VERSION 5.7 ;
BUSBITCHARS "[]" ;
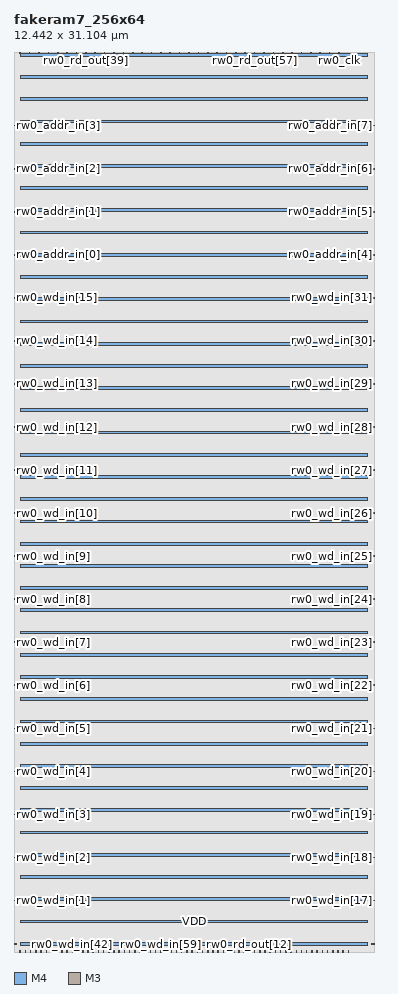
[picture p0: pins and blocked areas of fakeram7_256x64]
MACRO fakeram7_256x64
  FOREIGN fakeram7_256x64 0 0 ;
  SYMMETRY X Y R90 ;
  SIZE 12.442 BY 31.104 ;
  CLASS BLOCK ;
  PIN rw0_wd_in[0]
    DIRECTION INPUT ;
    USE SIGNAL ;
    SHAPE ABUTMENT ;
    PORT
      LAYER M4 ;
      RECT 0.000 0.276 0.072 0.300 ;
    END
  END rw0_wd_in[0]
  PIN rw0_wd_in[1]
    DIRECTION INPUT ;
    USE SIGNAL ;
    SHAPE ABUTMENT ;
    PORT
      LAYER M4 ;
      RECT 0.000 1.764 0.072 1.788 ;
    END
  END rw0_wd_in[1]
  PIN rw0_wd_in[2]
    DIRECTION INPUT ;
    USE SIGNAL ;
    SHAPE ABUTMENT ;
    PORT
      LAYER M4 ;
      RECT 0.000 3.252 0.072 3.276 ;
    END
  END rw0_wd_in[2]
  PIN rw0_wd_in[3]
    DIRECTION INPUT ;
    USE SIGNAL ;
    SHAPE ABUTMENT ;
    PORT
      LAYER M4 ;
      RECT 0.000 4.740 0.072 4.764 ;
    END
  END rw0_wd_in[3]
  PIN rw0_wd_in[4]
    DIRECTION INPUT ;
    USE SIGNAL ;
    SHAPE ABUTMENT ;
    PORT
      LAYER M4 ;
      RECT 0.000 6.228 0.072 6.252 ;
    END
  END rw0_wd_in[4]
  PIN rw0_wd_in[5]
    DIRECTION INPUT ;
    USE SIGNAL ;
    SHAPE ABUTMENT ;
    PORT
      LAYER M4 ;
      RECT 0.000 7.716 0.072 7.740 ;
    END
  END rw0_wd_in[5]
  PIN rw0_wd_in[6]
    DIRECTION INPUT ;
    USE SIGNAL ;
    SHAPE ABUTMENT ;
    PORT
      LAYER M4 ;
      RECT 0.000 9.204 0.072 9.228 ;
    END
  END rw0_wd_in[6]
  PIN rw0_wd_in[7]
    DIRECTION INPUT ;
    USE SIGNAL ;
    SHAPE ABUTMENT ;
    PORT
      LAYER M4 ;
      RECT 0.000 10.692 0.072 10.716 ;
    END
  END rw0_wd_in[7]
  PIN rw0_wd_in[8]
    DIRECTION INPUT ;
    USE SIGNAL ;
    SHAPE ABUTMENT ;
    PORT
      LAYER M4 ;
      RECT 0.000 12.180 0.072 12.204 ;
    END
  END rw0_wd_in[8]
  PIN rw0_wd_in[9]
    DIRECTION INPUT ;
    USE SIGNAL ;
    SHAPE ABUTMENT ;
    PORT
      LAYER M4 ;
      RECT 0.000 13.668 0.072 13.692 ;
    END
  END rw0_wd_in[9]
  PIN rw0_wd_in[10]
    DIRECTION INPUT ;
    USE SIGNAL ;
    SHAPE ABUTMENT ;
    PORT
      LAYER M4 ;
      RECT 0.000 15.156 0.072 15.180 ;
    END
  END rw0_wd_in[10]
  PIN rw0_wd_in[11]
    DIRECTION INPUT ;
    USE SIGNAL ;
    SHAPE ABUTMENT ;
    PORT
      LAYER M4 ;
      RECT 0.000 16.644 0.072 16.668 ;
    END
  END rw0_wd_in[11]
  PIN rw0_wd_in[12]
    DIRECTION INPUT ;
    USE SIGNAL ;
    SHAPE ABUTMENT ;
    PORT
      LAYER M4 ;
      RECT 0.000 18.132 0.072 18.156 ;
    END
  END rw0_wd_in[12]
  PIN rw0_wd_in[13]
    DIRECTION INPUT ;
    USE SIGNAL ;
    SHAPE ABUTMENT ;
    PORT
      LAYER M4 ;
      RECT 0.000 19.620 0.072 19.644 ;
    END
  END rw0_wd_in[13]
  PIN rw0_wd_in[14]
    DIRECTION INPUT ;
    USE SIGNAL ;
    SHAPE ABUTMENT ;
    PORT
      LAYER M4 ;
      RECT 0.000 21.108 0.072 21.132 ;
    END
  END rw0_wd_in[14]
  PIN rw0_wd_in[15]
    DIRECTION INPUT ;
    USE SIGNAL ;
    SHAPE ABUTMENT ;
    PORT
      LAYER M4 ;
      RECT 0.000 22.596 0.072 22.620 ;
    END
  END rw0_wd_in[15]
  PIN rw0_wd_in[16]
    DIRECTION INPUT ;
    USE SIGNAL ;
    SHAPE ABUTMENT ;
    PORT
      LAYER M4 ;
      RECT 12.370 0.276 12.442 0.300 ;
    END
  END rw0_wd_in[16]
  PIN rw0_wd_in[17]
    DIRECTION INPUT ;
    USE SIGNAL ;
    SHAPE ABUTMENT ;
    PORT
      LAYER M4 ;
      RECT 12.370 1.764 12.442 1.788 ;
    END
  END rw0_wd_in[17]
  PIN rw0_wd_in[18]
    DIRECTION INPUT ;
    USE SIGNAL ;
    SHAPE ABUTMENT ;
    PORT
      LAYER M4 ;
      RECT 12.370 3.252 12.442 3.276 ;
    END
  END rw0_wd_in[18]
  PIN rw0_wd_in[19]
    DIRECTION INPUT ;
    USE SIGNAL ;
    SHAPE ABUTMENT ;
    PORT
      LAYER M4 ;
      RECT 12.370 4.740 12.442 4.764 ;
    END
  END rw0_wd_in[19]
  PIN rw0_wd_in[20]
    DIRECTION INPUT ;
    USE SIGNAL ;
    SHAPE ABUTMENT ;
    PORT
      LAYER M4 ;
      RECT 12.370 6.228 12.442 6.252 ;
    END
  END rw0_wd_in[20]
  PIN rw0_wd_in[21]
    DIRECTION INPUT ;
    USE SIGNAL ;
    SHAPE ABUTMENT ;
    PORT
      LAYER M4 ;
      RECT 12.370 7.716 12.442 7.740 ;
    END
  END rw0_wd_in[21]
  PIN rw0_wd_in[22]
    DIRECTION INPUT ;
    USE SIGNAL ;
    SHAPE ABUTMENT ;
    PORT
      LAYER M4 ;
      RECT 12.370 9.204 12.442 9.228 ;
    END
  END rw0_wd_in[22]
  PIN rw0_wd_in[23]
    DIRECTION INPUT ;
    USE SIGNAL ;
    SHAPE ABUTMENT ;
    PORT
      LAYER M4 ;
      RECT 12.370 10.692 12.442 10.716 ;
    END
  END rw0_wd_in[23]
  PIN rw0_wd_in[24]
    DIRECTION INPUT ;
    USE SIGNAL ;
    SHAPE ABUTMENT ;
    PORT
      LAYER M4 ;
      RECT 12.370 12.180 12.442 12.204 ;
    END
  END rw0_wd_in[24]
  PIN rw0_wd_in[25]
    DIRECTION INPUT ;
    USE SIGNAL ;
    SHAPE ABUTMENT ;
    PORT
      LAYER M4 ;
      RECT 12.370 13.668 12.442 13.692 ;
    END
  END rw0_wd_in[25]
  PIN rw0_wd_in[26]
    DIRECTION INPUT ;
    USE SIGNAL ;
    SHAPE ABUTMENT ;
    PORT
      LAYER M4 ;
      RECT 12.370 15.156 12.442 15.180 ;
    END
  END rw0_wd_in[26]
  PIN rw0_wd_in[27]
    DIRECTION INPUT ;
    USE SIGNAL ;
    SHAPE ABUTMENT ;
    PORT
      LAYER M4 ;
      RECT 12.370 16.644 12.442 16.668 ;
    END
  END rw0_wd_in[27]
  PIN rw0_wd_in[28]
    DIRECTION INPUT ;
    USE SIGNAL ;
    SHAPE ABUTMENT ;
    PORT
      LAYER M4 ;
      RECT 12.370 18.132 12.442 18.156 ;
    END
  END rw0_wd_in[28]
  PIN rw0_wd_in[29]
    DIRECTION INPUT ;
    USE SIGNAL ;
    SHAPE ABUTMENT ;
    PORT
      LAYER M4 ;
      RECT 12.370 19.620 12.442 19.644 ;
    END
  END rw0_wd_in[29]
  PIN rw0_wd_in[30]
    DIRECTION INPUT ;
    USE SIGNAL ;
    SHAPE ABUTMENT ;
    PORT
      LAYER M4 ;
      RECT 12.370 21.108 12.442 21.132 ;
    END
  END rw0_wd_in[30]
  PIN rw0_wd_in[31]
    DIRECTION INPUT ;
    USE SIGNAL ;
    SHAPE ABUTMENT ;
    PORT
      LAYER M4 ;
      RECT 12.370 22.596 12.442 22.620 ;
    END
  END rw0_wd_in[31]
  PIN rw0_wd_in[32]
    DIRECTION OUTPUT ;
    USE SIGNAL ;
    SHAPE ABUTMENT ;
    PORT
      LAYER M3 ;
      RECT 0.207 0.000 0.225 0.054 ;
    END
  END rw0_wd_in[32]
  PIN rw0_wd_in[33]
    DIRECTION OUTPUT ;
    USE SIGNAL ;
    SHAPE ABUTMENT ;
    PORT
      LAYER M3 ;
      RECT 0.387 0.000 0.405 0.054 ;
    END
  END rw0_wd_in[33]
  PIN rw0_wd_in[34]
    DIRECTION OUTPUT ;
    USE SIGNAL ;
    SHAPE ABUTMENT ;
    PORT
      LAYER M3 ;
      RECT 0.567 0.000 0.585 0.054 ;
    END
  END rw0_wd_in[34]
  PIN rw0_wd_in[35]
    DIRECTION OUTPUT ;
    USE SIGNAL ;
    SHAPE ABUTMENT ;
    PORT
      LAYER M3 ;
      RECT 0.747 0.000 0.765 0.054 ;
    END
  END rw0_wd_in[35]
  PIN rw0_wd_in[36]
    DIRECTION OUTPUT ;
    USE SIGNAL ;
    SHAPE ABUTMENT ;
    PORT
      LAYER M3 ;
      RECT 0.927 0.000 0.945 0.054 ;
    END
  END rw0_wd_in[36]
  PIN rw0_wd_in[37]
    DIRECTION OUTPUT ;
    USE SIGNAL ;
    SHAPE ABUTMENT ;
    PORT
      LAYER M3 ;
      RECT 1.107 0.000 1.125 0.054 ;
    END
  END rw0_wd_in[37]
  PIN rw0_wd_in[38]
    DIRECTION OUTPUT ;
    USE SIGNAL ;
    SHAPE ABUTMENT ;
    PORT
      LAYER M3 ;
      RECT 1.287 0.000 1.305 0.054 ;
    END
  END rw0_wd_in[38]
  PIN rw0_wd_in[39]
    DIRECTION OUTPUT ;
    USE SIGNAL ;
    SHAPE ABUTMENT ;
    PORT
      LAYER M3 ;
      RECT 1.467 0.000 1.485 0.054 ;
    END
  END rw0_wd_in[39]
  PIN rw0_wd_in[40]
    DIRECTION OUTPUT ;
    USE SIGNAL ;
    SHAPE ABUTMENT ;
    PORT
      LAYER M3 ;
      RECT 1.647 0.000 1.665 0.054 ;
    END
  END rw0_wd_in[40]
  PIN rw0_wd_in[41]
    DIRECTION OUTPUT ;
    USE SIGNAL ;
    SHAPE ABUTMENT ;
    PORT
      LAYER M3 ;
      RECT 1.827 0.000 1.845 0.054 ;
    END
  END rw0_wd_in[41]
  PIN rw0_wd_in[42]
    DIRECTION OUTPUT ;
    USE SIGNAL ;
    SHAPE ABUTMENT ;
    PORT
      LAYER M3 ;
      RECT 2.007 0.000 2.025 0.054 ;
    END
  END rw0_wd_in[42]
  PIN rw0_wd_in[43]
    DIRECTION OUTPUT ;
    USE SIGNAL ;
    SHAPE ABUTMENT ;
    PORT
      LAYER M3 ;
      RECT 2.187 0.000 2.205 0.054 ;
    END
  END rw0_wd_in[43]
  PIN rw0_wd_in[44]
    DIRECTION OUTPUT ;
    USE SIGNAL ;
    SHAPE ABUTMENT ;
    PORT
      LAYER M3 ;
      RECT 2.367 0.000 2.385 0.054 ;
    END
  END rw0_wd_in[44]
  PIN rw0_wd_in[45]
    DIRECTION OUTPUT ;
    USE SIGNAL ;
    SHAPE ABUTMENT ;
    PORT
      LAYER M3 ;
      RECT 2.547 0.000 2.565 0.054 ;
    END
  END rw0_wd_in[45]
  PIN rw0_wd_in[46]
    DIRECTION OUTPUT ;
    USE SIGNAL ;
    SHAPE ABUTMENT ;
    PORT
      LAYER M3 ;
      RECT 2.727 0.000 2.745 0.054 ;
    END
  END rw0_wd_in[46]
  PIN rw0_wd_in[47]
    DIRECTION OUTPUT ;
    USE SIGNAL ;
    SHAPE ABUTMENT ;
    PORT
      LAYER M3 ;
      RECT 2.907 0.000 2.925 0.054 ;
    END
  END rw0_wd_in[47]
  PIN rw0_wd_in[48]
    DIRECTION OUTPUT ;
    USE SIGNAL ;
    SHAPE ABUTMENT ;
    PORT
      LAYER M3 ;
      RECT 3.087 0.000 3.105 0.054 ;
    END
  END rw0_wd_in[48]
  PIN rw0_wd_in[49]
    DIRECTION OUTPUT ;
    USE SIGNAL ;
    SHAPE ABUTMENT ;
    PORT
      LAYER M3 ;
      RECT 3.267 0.000 3.285 0.054 ;
    END
  END rw0_wd_in[49]
  PIN rw0_wd_in[50]
    DIRECTION OUTPUT ;
    USE SIGNAL ;
    SHAPE ABUTMENT ;
    PORT
      LAYER M3 ;
      RECT 3.447 0.000 3.465 0.054 ;
    END
  END rw0_wd_in[50]
  PIN rw0_wd_in[51]
    DIRECTION OUTPUT ;
    USE SIGNAL ;
    SHAPE ABUTMENT ;
    PORT
      LAYER M3 ;
      RECT 3.627 0.000 3.645 0.054 ;
    END
  END rw0_wd_in[51]
  PIN rw0_wd_in[52]
    DIRECTION OUTPUT ;
    USE SIGNAL ;
    SHAPE ABUTMENT ;
    PORT
      LAYER M3 ;
      RECT 3.807 0.000 3.825 0.054 ;
    END
  END rw0_wd_in[52]
  PIN rw0_wd_in[53]
    DIRECTION OUTPUT ;
    USE SIGNAL ;
    SHAPE ABUTMENT ;
    PORT
      LAYER M3 ;
      RECT 3.987 0.000 4.005 0.054 ;
    END
  END rw0_wd_in[53]
  PIN rw0_wd_in[54]
    DIRECTION OUTPUT ;
    USE SIGNAL ;
    SHAPE ABUTMENT ;
    PORT
      LAYER M3 ;
      RECT 4.167 0.000 4.185 0.054 ;
    END
  END rw0_wd_in[54]
  PIN rw0_wd_in[55]
    DIRECTION OUTPUT ;
    USE SIGNAL ;
    SHAPE ABUTMENT ;
    PORT
      LAYER M3 ;
      RECT 4.347 0.000 4.365 0.054 ;
    END
  END rw0_wd_in[55]
  PIN rw0_wd_in[56]
    DIRECTION OUTPUT ;
    USE SIGNAL ;
    SHAPE ABUTMENT ;
    PORT
      LAYER M3 ;
      RECT 4.527 0.000 4.545 0.054 ;
    END
  END rw0_wd_in[56]
  PIN rw0_wd_in[57]
    DIRECTION OUTPUT ;
    USE SIGNAL ;
    SHAPE ABUTMENT ;
    PORT
      LAYER M3 ;
      RECT 4.707 0.000 4.725 0.054 ;
    END
  END rw0_wd_in[57]
  PIN rw0_wd_in[58]
    DIRECTION OUTPUT ;
    USE SIGNAL ;
    SHAPE ABUTMENT ;
    PORT
      LAYER M3 ;
      RECT 4.887 0.000 4.905 0.054 ;
    END
  END rw0_wd_in[58]
  PIN rw0_wd_in[59]
    DIRECTION OUTPUT ;
    USE SIGNAL ;
    SHAPE ABUTMENT ;
    PORT
      LAYER M3 ;
      RECT 5.067 0.000 5.085 0.054 ;
    END
  END rw0_wd_in[59]
  PIN rw0_wd_in[60]
    DIRECTION OUTPUT ;
    USE SIGNAL ;
    SHAPE ABUTMENT ;
    PORT
      LAYER M3 ;
      RECT 5.247 0.000 5.265 0.054 ;
    END
  END rw0_wd_in[60]
  PIN rw0_wd_in[61]
    DIRECTION OUTPUT ;
    USE SIGNAL ;
    SHAPE ABUTMENT ;
    PORT
      LAYER M3 ;
      RECT 5.427 0.000 5.445 0.054 ;
    END
  END rw0_wd_in[61]
  PIN rw0_wd_in[62]
    DIRECTION OUTPUT ;
    USE SIGNAL ;
    SHAPE ABUTMENT ;
    PORT
      LAYER M3 ;
      RECT 5.607 0.000 5.625 0.054 ;
    END
  END rw0_wd_in[62]
  PIN rw0_wd_in[63]
    DIRECTION OUTPUT ;
    USE SIGNAL ;
    SHAPE ABUTMENT ;
    PORT
      LAYER M3 ;
      RECT 5.787 0.000 5.805 0.054 ;
    END
  END rw0_wd_in[63]
  PIN rw0_rd_out[0]
    DIRECTION OUTPUT ;
    USE SIGNAL ;
    SHAPE ABUTMENT ;
    PORT
      LAYER M3 ;
      RECT 5.967 0.000 5.985 0.054 ;
    END
  END rw0_rd_out[0]
  PIN rw0_rd_out[1]
    DIRECTION OUTPUT ;
    USE SIGNAL ;
    SHAPE ABUTMENT ;
    PORT
      LAYER M3 ;
      RECT 6.147 0.000 6.165 0.054 ;
    END
  END rw0_rd_out[1]
  PIN rw0_rd_out[2]
    DIRECTION OUTPUT ;
    USE SIGNAL ;
    SHAPE ABUTMENT ;
    PORT
      LAYER M3 ;
      RECT 6.327 0.000 6.345 0.054 ;
    END
  END rw0_rd_out[2]
  PIN rw0_rd_out[3]
    DIRECTION OUTPUT ;
    USE SIGNAL ;
    SHAPE ABUTMENT ;
    PORT
      LAYER M3 ;
      RECT 6.507 0.000 6.525 0.054 ;
    END
  END rw0_rd_out[3]
  PIN rw0_rd_out[4]
    DIRECTION OUTPUT ;
    USE SIGNAL ;
    SHAPE ABUTMENT ;
    PORT
      LAYER M3 ;
      RECT 6.687 0.000 6.705 0.054 ;
    END
  END rw0_rd_out[4]
  PIN rw0_rd_out[5]
    DIRECTION OUTPUT ;
    USE SIGNAL ;
    SHAPE ABUTMENT ;
    PORT
      LAYER M3 ;
      RECT 6.867 0.000 6.885 0.054 ;
    END
  END rw0_rd_out[5]
  PIN rw0_rd_out[6]
    DIRECTION OUTPUT ;
    USE SIGNAL ;
    SHAPE ABUTMENT ;
    PORT
      LAYER M3 ;
      RECT 7.047 0.000 7.065 0.054 ;
    END
  END rw0_rd_out[6]
  PIN rw0_rd_out[7]
    DIRECTION OUTPUT ;
    USE SIGNAL ;
    SHAPE ABUTMENT ;
    PORT
      LAYER M3 ;
      RECT 7.227 0.000 7.245 0.054 ;
    END
  END rw0_rd_out[7]
  PIN rw0_rd_out[8]
    DIRECTION OUTPUT ;
    USE SIGNAL ;
    SHAPE ABUTMENT ;
    PORT
      LAYER M3 ;
      RECT 7.407 0.000 7.425 0.054 ;
    END
  END rw0_rd_out[8]
  PIN rw0_rd_out[9]
    DIRECTION OUTPUT ;
    USE SIGNAL ;
    SHAPE ABUTMENT ;
    PORT
      LAYER M3 ;
      RECT 7.587 0.000 7.605 0.054 ;
    END
  END rw0_rd_out[9]
  PIN rw0_rd_out[10]
    DIRECTION OUTPUT ;
    USE SIGNAL ;
    SHAPE ABUTMENT ;
    PORT
      LAYER M3 ;
      RECT 7.767 0.000 7.785 0.054 ;
    END
  END rw0_rd_out[10]
  PIN rw0_rd_out[11]
    DIRECTION OUTPUT ;
    USE SIGNAL ;
    SHAPE ABUTMENT ;
    PORT
      LAYER M3 ;
      RECT 7.947 0.000 7.965 0.054 ;
    END
  END rw0_rd_out[11]
  PIN rw0_rd_out[12]
    DIRECTION OUTPUT ;
    USE SIGNAL ;
    SHAPE ABUTMENT ;
    PORT
      LAYER M3 ;
      RECT 8.127 0.000 8.145 0.054 ;
    END
  END rw0_rd_out[12]
  PIN rw0_rd_out[13]
    DIRECTION OUTPUT ;
    USE SIGNAL ;
    SHAPE ABUTMENT ;
    PORT
      LAYER M3 ;
      RECT 8.307 0.000 8.325 0.054 ;
    END
  END rw0_rd_out[13]
  PIN rw0_rd_out[14]
    DIRECTION OUTPUT ;
    USE SIGNAL ;
    SHAPE ABUTMENT ;
    PORT
      LAYER M3 ;
      RECT 8.487 0.000 8.505 0.054 ;
    END
  END rw0_rd_out[14]
  PIN rw0_rd_out[15]
    DIRECTION OUTPUT ;
    USE SIGNAL ;
    SHAPE ABUTMENT ;
    PORT
      LAYER M3 ;
      RECT 8.667 0.000 8.685 0.054 ;
    END
  END rw0_rd_out[15]
  PIN rw0_rd_out[16]
    DIRECTION OUTPUT ;
    USE SIGNAL ;
    SHAPE ABUTMENT ;
    PORT
      LAYER M3 ;
      RECT 8.847 0.000 8.865 0.054 ;
    END
  END rw0_rd_out[16]
  PIN rw0_rd_out[17]
    DIRECTION OUTPUT ;
    USE SIGNAL ;
    SHAPE ABUTMENT ;
    PORT
      LAYER M3 ;
      RECT 9.027 0.000 9.045 0.054 ;
    END
  END rw0_rd_out[17]
  PIN rw0_rd_out[18]
    DIRECTION OUTPUT ;
    USE SIGNAL ;
    SHAPE ABUTMENT ;
    PORT
      LAYER M3 ;
      RECT 9.207 0.000 9.225 0.054 ;
    END
  END rw0_rd_out[18]
  PIN rw0_rd_out[19]
    DIRECTION OUTPUT ;
    USE SIGNAL ;
    SHAPE ABUTMENT ;
    PORT
      LAYER M3 ;
      RECT 9.387 0.000 9.405 0.054 ;
    END
  END rw0_rd_out[19]
  PIN rw0_rd_out[20]
    DIRECTION OUTPUT ;
    USE SIGNAL ;
    SHAPE ABUTMENT ;
    PORT
      LAYER M3 ;
      RECT 9.567 0.000 9.585 0.054 ;
    END
  END rw0_rd_out[20]
  PIN rw0_rd_out[21]
    DIRECTION OUTPUT ;
    USE SIGNAL ;
    SHAPE ABUTMENT ;
    PORT
      LAYER M3 ;
      RECT 9.747 0.000 9.765 0.054 ;
    END
  END rw0_rd_out[21]
  PIN rw0_rd_out[22]
    DIRECTION OUTPUT ;
    USE SIGNAL ;
    SHAPE ABUTMENT ;
    PORT
      LAYER M3 ;
      RECT 9.927 0.000 9.945 0.054 ;
    END
  END rw0_rd_out[22]
  PIN rw0_rd_out[23]
    DIRECTION OUTPUT ;
    USE SIGNAL ;
    SHAPE ABUTMENT ;
    PORT
      LAYER M3 ;
      RECT 10.107 0.000 10.125 0.054 ;
    END
  END rw0_rd_out[23]
  PIN rw0_rd_out[24]
    DIRECTION OUTPUT ;
    USE SIGNAL ;
    SHAPE ABUTMENT ;
    PORT
      LAYER M3 ;
      RECT 10.287 0.000 10.305 0.054 ;
    END
  END rw0_rd_out[24]
  PIN rw0_rd_out[25]
    DIRECTION OUTPUT ;
    USE SIGNAL ;
    SHAPE ABUTMENT ;
    PORT
      LAYER M3 ;
      RECT 10.467 0.000 10.485 0.054 ;
    END
  END rw0_rd_out[25]
  PIN rw0_rd_out[26]
    DIRECTION OUTPUT ;
    USE SIGNAL ;
    SHAPE ABUTMENT ;
    PORT
      LAYER M3 ;
      RECT 10.647 0.000 10.665 0.054 ;
    END
  END rw0_rd_out[26]
  PIN rw0_rd_out[27]
    DIRECTION OUTPUT ;
    USE SIGNAL ;
    SHAPE ABUTMENT ;
    PORT
      LAYER M3 ;
      RECT 10.827 0.000 10.845 0.054 ;
    END
  END rw0_rd_out[27]
  PIN rw0_rd_out[28]
    DIRECTION OUTPUT ;
    USE SIGNAL ;
    SHAPE ABUTMENT ;
    PORT
      LAYER M3 ;
      RECT 11.007 0.000 11.025 0.054 ;
    END
  END rw0_rd_out[28]
  PIN rw0_rd_out[29]
    DIRECTION OUTPUT ;
    USE SIGNAL ;
    SHAPE ABUTMENT ;
    PORT
      LAYER M3 ;
      RECT 11.187 0.000 11.205 0.054 ;
    END
  END rw0_rd_out[29]
  PIN rw0_rd_out[30]
    DIRECTION OUTPUT ;
    USE SIGNAL ;
    SHAPE ABUTMENT ;
    PORT
      LAYER M3 ;
      RECT 11.367 0.000 11.385 0.054 ;
    END
  END rw0_rd_out[30]
  PIN rw0_rd_out[31]
    DIRECTION OUTPUT ;
    USE SIGNAL ;
    SHAPE ABUTMENT ;
    PORT
      LAYER M3 ;
      RECT 11.547 0.000 11.565 0.054 ;
    END
  END rw0_rd_out[31]
  PIN rw0_rd_out[32]
    DIRECTION OUTPUT ;
    USE SIGNAL ;
    SHAPE ABUTMENT ;
    PORT
      LAYER M3 ;
      RECT 0.207 31.050 0.225 31.104 ;
    END
  END rw0_rd_out[32]
  PIN rw0_rd_out[33]
    DIRECTION OUTPUT ;
    USE SIGNAL ;
    SHAPE ABUTMENT ;
    PORT
      LAYER M3 ;
      RECT 0.531 31.050 0.549 31.104 ;
    END
  END rw0_rd_out[33]
  PIN rw0_rd_out[34]
    DIRECTION OUTPUT ;
    USE SIGNAL ;
    SHAPE ABUTMENT ;
    PORT
      LAYER M3 ;
      RECT 0.855 31.050 0.873 31.104 ;
    END
  END rw0_rd_out[34]
  PIN rw0_rd_out[35]
    DIRECTION OUTPUT ;
    USE SIGNAL ;
    SHAPE ABUTMENT ;
    PORT
      LAYER M3 ;
      RECT 1.179 31.050 1.197 31.104 ;
    END
  END rw0_rd_out[35]
  PIN rw0_rd_out[36]
    DIRECTION OUTPUT ;
    USE SIGNAL ;
    SHAPE ABUTMENT ;
    PORT
      LAYER M3 ;
      RECT 1.503 31.050 1.521 31.104 ;
    END
  END rw0_rd_out[36]
  PIN rw0_rd_out[37]
    DIRECTION OUTPUT ;
    USE SIGNAL ;
    SHAPE ABUTMENT ;
    PORT
      LAYER M3 ;
      RECT 1.827 31.050 1.845 31.104 ;
    END
  END rw0_rd_out[37]
  PIN rw0_rd_out[38]
    DIRECTION OUTPUT ;
    USE SIGNAL ;
    SHAPE ABUTMENT ;
    PORT
      LAYER M3 ;
      RECT 2.151 31.050 2.169 31.104 ;
    END
  END rw0_rd_out[38]
  PIN rw0_rd_out[39]
    DIRECTION OUTPUT ;
    USE SIGNAL ;
    SHAPE ABUTMENT ;
    PORT
      LAYER M3 ;
      RECT 2.475 31.050 2.493 31.104 ;
    END
  END rw0_rd_out[39]
  PIN rw0_rd_out[40]
    DIRECTION OUTPUT ;
    USE SIGNAL ;
    SHAPE ABUTMENT ;
    PORT
      LAYER M3 ;
      RECT 2.799 31.050 2.817 31.104 ;
    END
  END rw0_rd_out[40]
  PIN rw0_rd_out[41]
    DIRECTION OUTPUT ;
    USE SIGNAL ;
    SHAPE ABUTMENT ;
    PORT
      LAYER M3 ;
      RECT 3.123 31.050 3.141 31.104 ;
    END
  END rw0_rd_out[41]
  PIN rw0_rd_out[42]
    DIRECTION OUTPUT ;
    USE SIGNAL ;
    SHAPE ABUTMENT ;
    PORT
      LAYER M3 ;
      RECT 3.447 31.050 3.465 31.104 ;
    END
  END rw0_rd_out[42]
  PIN rw0_rd_out[43]
    DIRECTION OUTPUT ;
    USE SIGNAL ;
    SHAPE ABUTMENT ;
    PORT
      LAYER M3 ;
      RECT 3.771 31.050 3.789 31.104 ;
    END
  END rw0_rd_out[43]
  PIN rw0_rd_out[44]
    DIRECTION OUTPUT ;
    USE SIGNAL ;
    SHAPE ABUTMENT ;
    PORT
      LAYER M3 ;
      RECT 4.095 31.050 4.113 31.104 ;
    END
  END rw0_rd_out[44]
  PIN rw0_rd_out[45]
    DIRECTION OUTPUT ;
    USE SIGNAL ;
    SHAPE ABUTMENT ;
    PORT
      LAYER M3 ;
      RECT 4.419 31.050 4.437 31.104 ;
    END
  END rw0_rd_out[45]
  PIN rw0_rd_out[46]
    DIRECTION OUTPUT ;
    USE SIGNAL ;
    SHAPE ABUTMENT ;
    PORT
      LAYER M3 ;
      RECT 4.743 31.050 4.761 31.104 ;
    END
  END rw0_rd_out[46]
  PIN rw0_rd_out[47]
    DIRECTION OUTPUT ;
    USE SIGNAL ;
    SHAPE ABUTMENT ;
    PORT
      LAYER M3 ;
      RECT 5.067 31.050 5.085 31.104 ;
    END
  END rw0_rd_out[47]
  PIN rw0_rd_out[48]
    DIRECTION OUTPUT ;
    USE SIGNAL ;
    SHAPE ABUTMENT ;
    PORT
      LAYER M3 ;
      RECT 5.391 31.050 5.409 31.104 ;
    END
  END rw0_rd_out[48]
  PIN rw0_rd_out[49]
    DIRECTION OUTPUT ;
    USE SIGNAL ;
    SHAPE ABUTMENT ;
    PORT
      LAYER M3 ;
      RECT 5.715 31.050 5.733 31.104 ;
    END
  END rw0_rd_out[49]
  PIN rw0_rd_out[50]
    DIRECTION OUTPUT ;
    USE SIGNAL ;
    SHAPE ABUTMENT ;
    PORT
      LAYER M3 ;
      RECT 6.039 31.050 6.057 31.104 ;
    END
  END rw0_rd_out[50]
  PIN rw0_rd_out[51]
    DIRECTION OUTPUT ;
    USE SIGNAL ;
    SHAPE ABUTMENT ;
    PORT
      LAYER M3 ;
      RECT 6.363 31.050 6.381 31.104 ;
    END
  END rw0_rd_out[51]
  PIN rw0_rd_out[52]
    DIRECTION OUTPUT ;
    USE SIGNAL ;
    SHAPE ABUTMENT ;
    PORT
      LAYER M3 ;
      RECT 6.687 31.050 6.705 31.104 ;
    END
  END rw0_rd_out[52]
  PIN rw0_rd_out[53]
    DIRECTION OUTPUT ;
    USE SIGNAL ;
    SHAPE ABUTMENT ;
    PORT
      LAYER M3 ;
      RECT 7.011 31.050 7.029 31.104 ;
    END
  END rw0_rd_out[53]
  PIN rw0_rd_out[54]
    DIRECTION OUTPUT ;
    USE SIGNAL ;
    SHAPE ABUTMENT ;
    PORT
      LAYER M3 ;
      RECT 7.335 31.050 7.353 31.104 ;
    END
  END rw0_rd_out[54]
  PIN rw0_rd_out[55]
    DIRECTION OUTPUT ;
    USE SIGNAL ;
    SHAPE ABUTMENT ;
    PORT
      LAYER M3 ;
      RECT 7.659 31.050 7.677 31.104 ;
    END
  END rw0_rd_out[55]
  PIN rw0_rd_out[56]
    DIRECTION OUTPUT ;
    USE SIGNAL ;
    SHAPE ABUTMENT ;
    PORT
      LAYER M3 ;
      RECT 7.983 31.050 8.001 31.104 ;
    END
  END rw0_rd_out[56]
  PIN rw0_rd_out[57]
    DIRECTION OUTPUT ;
    USE SIGNAL ;
    SHAPE ABUTMENT ;
    PORT
      LAYER M3 ;
      RECT 8.307 31.050 8.325 31.104 ;
    END
  END rw0_rd_out[57]
  PIN rw0_rd_out[58]
    DIRECTION OUTPUT ;
    USE SIGNAL ;
    SHAPE ABUTMENT ;
    PORT
      LAYER M3 ;
      RECT 8.631 31.050 8.649 31.104 ;
    END
  END rw0_rd_out[58]
  PIN rw0_rd_out[59]
    DIRECTION OUTPUT ;
    USE SIGNAL ;
    SHAPE ABUTMENT ;
    PORT
      LAYER M3 ;
      RECT 8.955 31.050 8.973 31.104 ;
    END
  END rw0_rd_out[59]
  PIN rw0_rd_out[60]
    DIRECTION OUTPUT ;
    USE SIGNAL ;
    SHAPE ABUTMENT ;
    PORT
      LAYER M3 ;
      RECT 9.279 31.050 9.297 31.104 ;
    END
  END rw0_rd_out[60]
  PIN rw0_rd_out[61]
    DIRECTION OUTPUT ;
    USE SIGNAL ;
    SHAPE ABUTMENT ;
    PORT
      LAYER M3 ;
      RECT 9.603 31.050 9.621 31.104 ;
    END
  END rw0_rd_out[61]
  PIN rw0_rd_out[62]
    DIRECTION OUTPUT ;
    USE SIGNAL ;
    SHAPE ABUTMENT ;
    PORT
      LAYER M3 ;
      RECT 9.927 31.050 9.945 31.104 ;
    END
  END rw0_rd_out[62]
  PIN rw0_rd_out[63]
    DIRECTION OUTPUT ;
    USE SIGNAL ;
    SHAPE ABUTMENT ;
    PORT
      LAYER M3 ;
      RECT 10.251 31.050 10.269 31.104 ;
    END
  END rw0_rd_out[63]
  PIN rw0_addr_in[0]
    DIRECTION INPUT ;
    USE SIGNAL ;
    SHAPE ABUTMENT ;
    PORT
      LAYER M4 ;
      RECT 0.000 24.084 0.072 24.108 ;
    END
  END rw0_addr_in[0]
  PIN rw0_addr_in[1]
    DIRECTION INPUT ;
    USE SIGNAL ;
    SHAPE ABUTMENT ;
    PORT
      LAYER M4 ;
      RECT 0.000 25.572 0.072 25.596 ;
    END
  END rw0_addr_in[1]
  PIN rw0_addr_in[2]
    DIRECTION INPUT ;
    USE SIGNAL ;
    SHAPE ABUTMENT ;
    PORT
      LAYER M4 ;
      RECT 0.000 27.060 0.072 27.084 ;
    END
  END rw0_addr_in[2]
  PIN rw0_addr_in[3]
    DIRECTION INPUT ;
    USE SIGNAL ;
    SHAPE ABUTMENT ;
    PORT
      LAYER M4 ;
      RECT 0.000 28.548 0.072 28.572 ;
    END
  END rw0_addr_in[3]
  PIN rw0_addr_in[4]
    DIRECTION INPUT ;
    USE SIGNAL ;
    SHAPE ABUTMENT ;
    PORT
      LAYER M4 ;
      RECT 12.370 24.084 12.442 24.108 ;
    END
  END rw0_addr_in[4]
  PIN rw0_addr_in[5]
    DIRECTION INPUT ;
    USE SIGNAL ;
    SHAPE ABUTMENT ;
    PORT
      LAYER M4 ;
      RECT 12.370 25.572 12.442 25.596 ;
    END
  END rw0_addr_in[5]
  PIN rw0_addr_in[6]
    DIRECTION INPUT ;
    USE SIGNAL ;
    SHAPE ABUTMENT ;
    PORT
      LAYER M4 ;
      RECT 12.370 27.060 12.442 27.084 ;
    END
  END rw0_addr_in[6]
  PIN rw0_addr_in[7]
    DIRECTION INPUT ;
    USE SIGNAL ;
    SHAPE ABUTMENT ;
    PORT
      LAYER M4 ;
      RECT 12.370 28.548 12.442 28.572 ;
    END
  END rw0_addr_in[7]
  PIN rw0_we_in
    DIRECTION INPUT ;
    USE SIGNAL ;
    SHAPE ABUTMENT ;
    PORT
      LAYER M3 ;
      RECT 10.575 31.050 10.593 31.104 ;
    END
  END rw0_we_in
  PIN rw0_ce_in
    DIRECTION INPUT ;
    USE SIGNAL ;
    SHAPE ABUTMENT ;
    PORT
      LAYER M3 ;
      RECT 10.899 31.050 10.917 31.104 ;
    END
  END rw0_ce_in
  PIN rw0_clk
    DIRECTION INPUT ;
    USE SIGNAL ;
    SHAPE ABUTMENT ;
    PORT
      LAYER M3 ;
      RECT 11.223 31.050 11.241 31.104 ;
    END
  END rw0_clk
  PIN VSS
    DIRECTION INOUT ;
    USE GROUND ;
    PORT
      LAYER M4 ;
      RECT 0.216 0.240 12.226 0.336 ;
      RECT 0.216 1.008 12.226 1.104 ;
      RECT 0.216 1.776 12.226 1.872 ;
      RECT 0.216 2.544 12.226 2.640 ;
      RECT 0.216 3.312 12.226 3.408 ;
      RECT 0.216 4.080 12.226 4.176 ;
      RECT 0.216 4.848 12.226 4.944 ;
      RECT 0.216 5.616 12.226 5.712 ;
      RECT 0.216 6.384 12.226 6.480 ;
      RECT 0.216 7.152 12.226 7.248 ;
      RECT 0.216 7.920 12.226 8.016 ;
      RECT 0.216 8.688 12.226 8.784 ;
      RECT 0.216 9.456 12.226 9.552 ;
      RECT 0.216 10.224 12.226 10.320 ;
      RECT 0.216 10.992 12.226 11.088 ;
      RECT 0.216 11.760 12.226 11.856 ;
      RECT 0.216 12.528 12.226 12.624 ;
      RECT 0.216 13.296 12.226 13.392 ;
      RECT 0.216 14.064 12.226 14.160 ;
      RECT 0.216 14.832 12.226 14.928 ;
      RECT 0.216 15.600 12.226 15.696 ;
      RECT 0.216 16.368 12.226 16.464 ;
      RECT 0.216 17.136 12.226 17.232 ;
      RECT 0.216 17.904 12.226 18.000 ;
      RECT 0.216 18.672 12.226 18.768 ;
      RECT 0.216 19.440 12.226 19.536 ;
      RECT 0.216 20.208 12.226 20.304 ;
      RECT 0.216 20.976 12.226 21.072 ;
      RECT 0.216 21.744 12.226 21.840 ;
      RECT 0.216 22.512 12.226 22.608 ;
      RECT 0.216 23.280 12.226 23.376 ;
      RECT 0.216 24.048 12.226 24.144 ;
      RECT 0.216 24.816 12.226 24.912 ;
      RECT 0.216 25.584 12.226 25.680 ;
      RECT 0.216 26.352 12.226 26.448 ;
      RECT 0.216 27.120 12.226 27.216 ;
      RECT 0.216 27.888 12.226 27.984 ;
      RECT 0.216 28.656 12.226 28.752 ;
      RECT 0.216 29.424 12.226 29.520 ;
      RECT 0.216 30.192 12.226 30.288 ;
      RECT 0.216 30.960 12.226 31.056 ;
    END
  END VSS
  PIN VDD
    DIRECTION INOUT ;
    USE POWER ;
    PORT
      LAYER M4 ;
      RECT 0.216 0.240 12.226 0.336 ;
      RECT 0.216 1.008 12.226 1.104 ;
      RECT 0.216 1.776 12.226 1.872 ;
      RECT 0.216 2.544 12.226 2.640 ;
      RECT 0.216 3.312 12.226 3.408 ;
      RECT 0.216 4.080 12.226 4.176 ;
      RECT 0.216 4.848 12.226 4.944 ;
      RECT 0.216 5.616 12.226 5.712 ;
      RECT 0.216 6.384 12.226 6.480 ;
      RECT 0.216 7.152 12.226 7.248 ;
      RECT 0.216 7.920 12.226 8.016 ;
      RECT 0.216 8.688 12.226 8.784 ;
      RECT 0.216 9.456 12.226 9.552 ;
      RECT 0.216 10.224 12.226 10.320 ;
      RECT 0.216 10.992 12.226 11.088 ;
      RECT 0.216 11.760 12.226 11.856 ;
      RECT 0.216 12.528 12.226 12.624 ;
      RECT 0.216 13.296 12.226 13.392 ;
      RECT 0.216 14.064 12.226 14.160 ;
      RECT 0.216 14.832 12.226 14.928 ;
      RECT 0.216 15.600 12.226 15.696 ;
      RECT 0.216 16.368 12.226 16.464 ;
      RECT 0.216 17.136 12.226 17.232 ;
      RECT 0.216 17.904 12.226 18.000 ;
      RECT 0.216 18.672 12.226 18.768 ;
      RECT 0.216 19.440 12.226 19.536 ;
      RECT 0.216 20.208 12.226 20.304 ;
      RECT 0.216 20.976 12.226 21.072 ;
      RECT 0.216 21.744 12.226 21.840 ;
      RECT 0.216 22.512 12.226 22.608 ;
      RECT 0.216 23.280 12.226 23.376 ;
      RECT 0.216 24.048 12.226 24.144 ;
      RECT 0.216 24.816 12.226 24.912 ;
      RECT 0.216 25.584 12.226 25.680 ;
      RECT 0.216 26.352 12.226 26.448 ;
      RECT 0.216 27.120 12.226 27.216 ;
      RECT 0.216 27.888 12.226 27.984 ;
      RECT 0.216 28.656 12.226 28.752 ;
      RECT 0.216 29.424 12.226 29.520 ;
      RECT 0.216 30.192 12.226 30.288 ;
      RECT 0.216 30.960 12.226 31.056 ;
    END
  END VDD
  OBS
    LAYER M1 ;
    RECT 0 0 12.442 31.104 ;
    LAYER M2 ;
    RECT 0 0 12.442 31.104 ;
    LAYER M3 ;
    RECT 0 0 12.442 31.104 ;
    LAYER M4 ;
    RECT 0 0 12.442 31.104 ;
  END
END fakeram7_256x64

END LIBRARY
